VERSION 5.7 ;
  NOWIREEXTENSIONATPIN ON ;
  DIVIDERCHAR "/" ;
  BUSBITCHARS "[]" ;
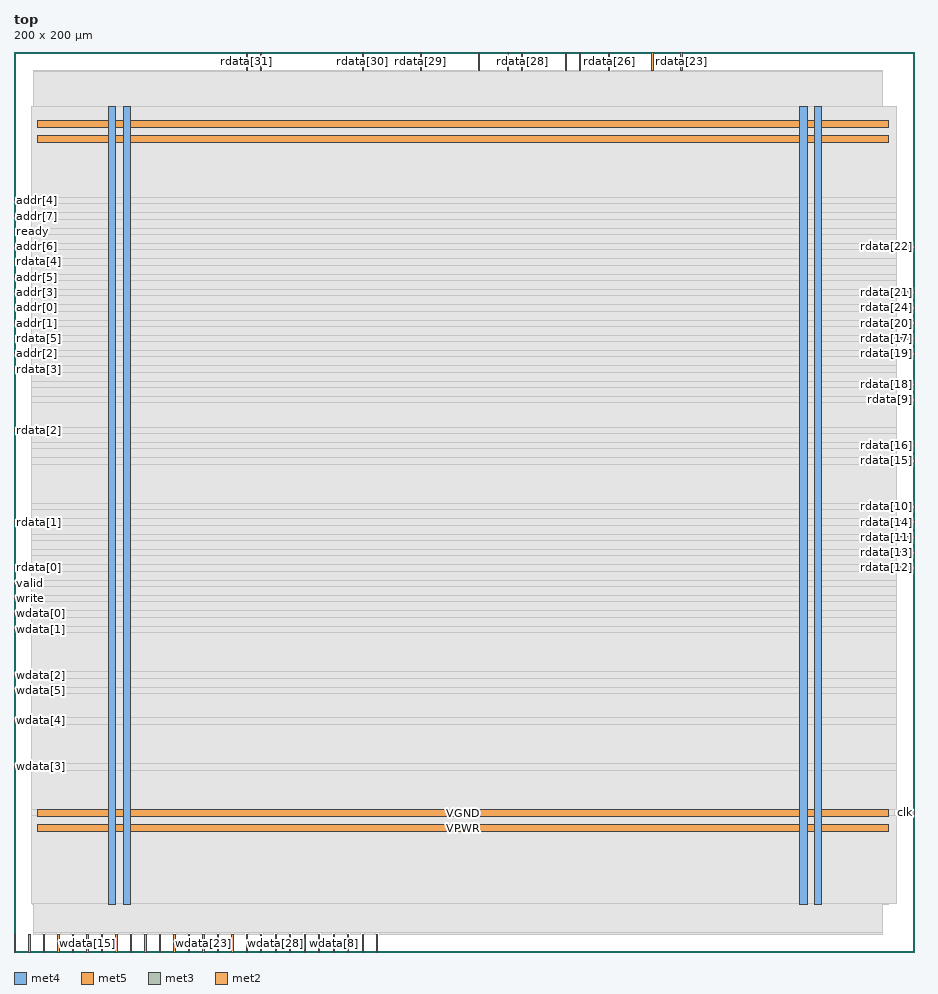
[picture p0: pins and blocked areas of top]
MACRO top
  CLASS BLOCK ;
  FOREIGN top ;
  ORIGIN 0.000 0.000 ;
  SIZE 200.000 BY 200.000 ;
  PIN VGND
    DIRECTION INOUT ;
    USE GROUND ;
    PORT
      LAYER met4 ;
        RECT 24.340 10.640 25.940 187.920 ;
    END
    PORT
      LAYER met4 ;
        RECT 177.940 10.640 179.540 187.920 ;
    END
    PORT
      LAYER met5 ;
        RECT 5.280 30.030 194.360 31.630 ;
    END
    PORT
      LAYER met5 ;
        RECT 5.280 183.210 194.360 184.810 ;
    END
  END VGND
  PIN VPWR
    DIRECTION INOUT ;
    USE POWER ;
    PORT
      LAYER met4 ;
        RECT 21.040 10.640 22.640 187.920 ;
    END
    PORT
      LAYER met4 ;
        RECT 174.640 10.640 176.240 187.920 ;
    END
    PORT
      LAYER met5 ;
        RECT 5.280 26.730 194.360 28.330 ;
    END
    PORT
      LAYER met5 ;
        RECT 5.280 179.910 194.360 181.510 ;
    END
  END VPWR
  PIN addr[0]
    DIRECTION INPUT ;
    USE SIGNAL ;
    ANTENNAGATEAREA 0.196500 ;
    PORT
      LAYER met3 ;
        RECT 0.000 142.840 4.000 143.440 ;
    END
  END addr[0]
  PIN addr[1]
    DIRECTION INPUT ;
    USE SIGNAL ;
    ANTENNAGATEAREA 0.196500 ;
    PORT
      LAYER met3 ;
        RECT 0.000 139.440 4.000 140.040 ;
    END
  END addr[1]
  PIN addr[2]
    DIRECTION INPUT ;
    USE SIGNAL ;
    ANTENNAGATEAREA 0.196500 ;
    PORT
      LAYER met3 ;
        RECT 0.000 132.640 4.000 133.240 ;
    END
  END addr[2]
  PIN addr[3]
    DIRECTION INPUT ;
    USE SIGNAL ;
    ANTENNAGATEAREA 0.196500 ;
    PORT
      LAYER met3 ;
        RECT 0.000 146.240 4.000 146.840 ;
    END
  END addr[3]
  PIN addr[4]
    DIRECTION INPUT ;
    USE SIGNAL ;
    ANTENNAGATEAREA 0.196500 ;
    PORT
      LAYER met3 ;
        RECT 0.000 166.640 4.000 167.240 ;
    END
  END addr[4]
  PIN addr[5]
    DIRECTION INPUT ;
    USE SIGNAL ;
    ANTENNAGATEAREA 0.196500 ;
    PORT
      LAYER met3 ;
        RECT 0.000 149.640 4.000 150.240 ;
    END
  END addr[5]
  PIN addr[6]
    DIRECTION INPUT ;
    USE SIGNAL ;
    ANTENNAGATEAREA 0.196500 ;
    PORT
      LAYER met3 ;
        RECT 0.000 156.440 4.000 157.040 ;
    END
  END addr[6]
  PIN addr[7]
    DIRECTION INPUT ;
    USE SIGNAL ;
    ANTENNAGATEAREA 0.196500 ;
    PORT
      LAYER met3 ;
        RECT 0.000 163.240 4.000 163.840 ;
    END
  END addr[7]
  PIN clk
    DIRECTION INPUT ;
    USE SIGNAL ;
    ANTENNAGATEAREA 0.852000 ;
    PORT
      LAYER met3 ;
        RECT 196.000 30.640 200.000 31.240 ;
    END
  END clk
  PIN rdata[0]
    DIRECTION OUTPUT ;
    USE SIGNAL ;
    ANTENNADIFFAREA 0.445500 ;
    PORT
      LAYER met3 ;
        RECT 0.000 85.040 4.000 85.640 ;
    END
  END rdata[0]
  PIN rdata[10]
    DIRECTION OUTPUT ;
    USE SIGNAL ;
    ANTENNADIFFAREA 0.445500 ;
    PORT
      LAYER met3 ;
        RECT 196.000 98.640 200.000 99.240 ;
    END
  END rdata[10]
  PIN rdata[11]
    DIRECTION OUTPUT ;
    USE SIGNAL ;
    ANTENNADIFFAREA 0.445500 ;
    PORT
      LAYER met3 ;
        RECT 196.000 91.840 200.000 92.440 ;
    END
  END rdata[11]
  PIN rdata[12]
    DIRECTION OUTPUT ;
    USE SIGNAL ;
    ANTENNADIFFAREA 0.445500 ;
    PORT
      LAYER met3 ;
        RECT 196.000 85.040 200.000 85.640 ;
    END
  END rdata[12]
  PIN rdata[13]
    DIRECTION OUTPUT ;
    USE SIGNAL ;
    ANTENNADIFFAREA 0.445500 ;
    PORT
      LAYER met3 ;
        RECT 196.000 88.440 200.000 89.040 ;
    END
  END rdata[13]
  PIN rdata[14]
    DIRECTION OUTPUT ;
    USE SIGNAL ;
    ANTENNADIFFAREA 0.445500 ;
    PORT
      LAYER met3 ;
        RECT 196.000 95.240 200.000 95.840 ;
    END
  END rdata[14]
  PIN rdata[15]
    DIRECTION OUTPUT ;
    USE SIGNAL ;
    ANTENNADIFFAREA 0.445500 ;
    PORT
      LAYER met3 ;
        RECT 196.000 108.840 200.000 109.440 ;
    END
  END rdata[15]
  PIN rdata[16]
    DIRECTION OUTPUT ;
    USE SIGNAL ;
    ANTENNADIFFAREA 0.445500 ;
    PORT
      LAYER met3 ;
        RECT 196.000 112.240 200.000 112.840 ;
    END
  END rdata[16]
  PIN rdata[17]
    DIRECTION OUTPUT ;
    USE SIGNAL ;
    ANTENNADIFFAREA 0.445500 ;
    PORT
      LAYER met3 ;
        RECT 196.000 136.040 200.000 136.640 ;
    END
  END rdata[17]
  PIN rdata[18]
    DIRECTION OUTPUT ;
    USE SIGNAL ;
    ANTENNADIFFAREA 0.445500 ;
    PORT
      LAYER met3 ;
        RECT 196.000 125.840 200.000 126.440 ;
    END
  END rdata[18]
  PIN rdata[19]
    DIRECTION OUTPUT ;
    USE SIGNAL ;
    ANTENNADIFFAREA 0.445500 ;
    PORT
      LAYER met3 ;
        RECT 196.000 132.640 200.000 133.240 ;
    END
  END rdata[19]
  PIN rdata[1]
    DIRECTION OUTPUT ;
    USE SIGNAL ;
    ANTENNADIFFAREA 0.445500 ;
    PORT
      LAYER met3 ;
        RECT 0.000 95.240 4.000 95.840 ;
    END
  END rdata[1]
  PIN rdata[20]
    DIRECTION OUTPUT ;
    USE SIGNAL ;
    ANTENNADIFFAREA 0.445500 ;
    PORT
      LAYER met3 ;
        RECT 196.000 139.440 200.000 140.040 ;
    END
  END rdata[20]
  PIN rdata[21]
    DIRECTION OUTPUT ;
    USE SIGNAL ;
    ANTENNADIFFAREA 0.445500 ;
    PORT
      LAYER met3 ;
        RECT 196.000 146.240 200.000 146.840 ;
    END
  END rdata[21]
  PIN rdata[22]
    DIRECTION OUTPUT ;
    USE SIGNAL ;
    ANTENNADIFFAREA 0.445500 ;
    PORT
      LAYER met3 ;
        RECT 196.000 156.440 200.000 157.040 ;
    END
  END rdata[22]
  PIN rdata[23]
    DIRECTION OUTPUT ;
    USE SIGNAL ;
    ANTENNADIFFAREA 0.445500 ;
    PORT
      LAYER met2 ;
        RECT 148.210 196.000 148.490 200.000 ;
    END
  END rdata[23]
  PIN rdata[24]
    DIRECTION OUTPUT ;
    USE SIGNAL ;
    ANTENNADIFFAREA 0.445500 ;
    PORT
      LAYER met3 ;
        RECT 196.000 142.840 200.000 143.440 ;
    END
  END rdata[24]
  PIN rdata[25]
    DIRECTION OUTPUT ;
    USE SIGNAL ;
    ANTENNADIFFAREA 0.445500 ;
    PORT
      LAYER met2 ;
        RECT 122.450 196.000 122.730 200.000 ;
    END
  END rdata[25]
  PIN rdata[26]
    DIRECTION OUTPUT ;
    USE SIGNAL ;
    ANTENNADIFFAREA 0.445500 ;
    PORT
      LAYER met2 ;
        RECT 132.110 196.000 132.390 200.000 ;
    END
  END rdata[26]
  PIN rdata[27]
    DIRECTION OUTPUT ;
    USE SIGNAL ;
    ANTENNADIFFAREA 0.445500 ;
    PORT
      LAYER met2 ;
        RECT 109.570 196.000 109.850 200.000 ;
    END
  END rdata[27]
  PIN rdata[28]
    DIRECTION OUTPUT ;
    USE SIGNAL ;
    ANTENNADIFFAREA 0.445500 ;
    PORT
      LAYER met2 ;
        RECT 112.790 196.000 113.070 200.000 ;
    END
  END rdata[28]
  PIN rdata[29]
    DIRECTION OUTPUT ;
    USE SIGNAL ;
    ANTENNADIFFAREA 0.445500 ;
    PORT
      LAYER met2 ;
        RECT 90.250 196.000 90.530 200.000 ;
    END
  END rdata[29]
  PIN rdata[2]
    DIRECTION OUTPUT ;
    USE SIGNAL ;
    ANTENNADIFFAREA 0.445500 ;
    PORT
      LAYER met3 ;
        RECT 0.000 115.640 4.000 116.240 ;
    END
  END rdata[2]
  PIN rdata[30]
    DIRECTION OUTPUT ;
    USE SIGNAL ;
    ANTENNADIFFAREA 0.445500 ;
    PORT
      LAYER met2 ;
        RECT 77.370 196.000 77.650 200.000 ;
    END
  END rdata[30]
  PIN rdata[31]
    DIRECTION OUTPUT ;
    USE SIGNAL ;
    ANTENNADIFFAREA 0.445500 ;
    PORT
      LAYER met2 ;
        RECT 51.610 196.000 51.890 200.000 ;
    END
  END rdata[31]
  PIN rdata[3]
    DIRECTION OUTPUT ;
    USE SIGNAL ;
    ANTENNADIFFAREA 0.445500 ;
    PORT
      LAYER met3 ;
        RECT 0.000 129.240 4.000 129.840 ;
    END
  END rdata[3]
  PIN rdata[4]
    DIRECTION OUTPUT ;
    USE SIGNAL ;
    ANTENNADIFFAREA 0.445500 ;
    PORT
      LAYER met3 ;
        RECT 0.000 153.040 4.000 153.640 ;
    END
  END rdata[4]
  PIN rdata[5]
    DIRECTION OUTPUT ;
    USE SIGNAL ;
    ANTENNADIFFAREA 0.445500 ;
    PORT
      LAYER met3 ;
        RECT 0.000 136.040 4.000 136.640 ;
    END
  END rdata[5]
  PIN rdata[6]
    DIRECTION OUTPUT ;
    USE SIGNAL ;
    ANTENNADIFFAREA 0.445500 ;
    PORT
      LAYER met2 ;
        RECT 54.830 196.000 55.110 200.000 ;
    END
  END rdata[6]
  PIN rdata[7]
    DIRECTION OUTPUT ;
    USE SIGNAL ;
    ANTENNADIFFAREA 0.445500 ;
    PORT
      LAYER met2 ;
        RECT 103.130 196.000 103.410 200.000 ;
    END
  END rdata[7]
  PIN rdata[8]
    DIRECTION OUTPUT ;
    USE SIGNAL ;
    ANTENNADIFFAREA 0.445500 ;
    PORT
      LAYER met2 ;
        RECT 125.670 196.000 125.950 200.000 ;
    END
  END rdata[8]
  PIN rdata[9]
    DIRECTION OUTPUT ;
    USE SIGNAL ;
    ANTENNADIFFAREA 0.445500 ;
    PORT
      LAYER met3 ;
        RECT 196.000 122.440 200.000 123.040 ;
    END
  END rdata[9]
  PIN ready
    DIRECTION OUTPUT ;
    USE SIGNAL ;
    PORT
      LAYER met3 ;
        RECT 0.000 159.840 4.000 160.440 ;
    END
  END ready
  PIN rst
    DIRECTION INPUT ;
    USE SIGNAL ;
    ANTENNAGATEAREA 0.213000 ;
    PORT
      LAYER met2 ;
        RECT 141.770 196.000 142.050 200.000 ;
    END
  END rst
  PIN valid
    DIRECTION INPUT ;
    USE SIGNAL ;
    ANTENNAGATEAREA 0.213000 ;
    PORT
      LAYER met3 ;
        RECT 0.000 81.640 4.000 82.240 ;
    END
  END valid
  PIN wdata[0]
    DIRECTION INPUT ;
    USE SIGNAL ;
    ANTENNAGATEAREA 0.196500 ;
    PORT
      LAYER met3 ;
        RECT 0.000 74.840 4.000 75.440 ;
    END
  END wdata[0]
  PIN wdata[10]
    DIRECTION INPUT ;
    USE SIGNAL ;
    PORT
      LAYER met2 ;
        RECT 3.310 0.000 3.590 4.000 ;
    END
  END wdata[10]
  PIN wdata[11]
    DIRECTION INPUT ;
    USE SIGNAL ;
    PORT
      LAYER met2 ;
        RECT 6.530 0.000 6.810 4.000 ;
    END
  END wdata[11]
  PIN wdata[12]
    DIRECTION INPUT ;
    USE SIGNAL ;
    PORT
      LAYER met2 ;
        RECT 9.750 0.000 10.030 4.000 ;
    END
  END wdata[12]
  PIN wdata[13]
    DIRECTION INPUT ;
    USE SIGNAL ;
    PORT
      LAYER met2 ;
        RECT 12.970 0.000 13.250 4.000 ;
    END
  END wdata[13]
  PIN wdata[14]
    DIRECTION INPUT ;
    USE SIGNAL ;
    PORT
      LAYER met2 ;
        RECT 80.590 0.000 80.870 4.000 ;
    END
  END wdata[14]
  PIN wdata[15]
    DIRECTION INPUT ;
    USE SIGNAL ;
    PORT
      LAYER met2 ;
        RECT 16.190 0.000 16.470 4.000 ;
    END
  END wdata[15]
  PIN wdata[16]
    DIRECTION INPUT ;
    USE SIGNAL ;
    PORT
      LAYER met2 ;
        RECT 19.410 0.000 19.690 4.000 ;
    END
  END wdata[16]
  PIN wdata[17]
    DIRECTION INPUT ;
    USE SIGNAL ;
    PORT
      LAYER met2 ;
        RECT 22.630 0.000 22.910 4.000 ;
    END
  END wdata[17]
  PIN wdata[18]
    DIRECTION INPUT ;
    USE SIGNAL ;
    PORT
      LAYER met2 ;
        RECT 25.850 0.000 26.130 4.000 ;
    END
  END wdata[18]
  PIN wdata[19]
    DIRECTION INPUT ;
    USE SIGNAL ;
    PORT
      LAYER met2 ;
        RECT 29.070 0.000 29.350 4.000 ;
    END
  END wdata[19]
  PIN wdata[1]
    DIRECTION INPUT ;
    USE SIGNAL ;
    ANTENNAGATEAREA 0.196500 ;
    PORT
      LAYER met3 ;
        RECT 0.000 71.440 4.000 72.040 ;
    END
  END wdata[1]
  PIN wdata[20]
    DIRECTION INPUT ;
    USE SIGNAL ;
    PORT
      LAYER met2 ;
        RECT 32.290 0.000 32.570 4.000 ;
    END
  END wdata[20]
  PIN wdata[21]
    DIRECTION INPUT ;
    USE SIGNAL ;
    PORT
      LAYER met2 ;
        RECT 35.510 0.000 35.790 4.000 ;
    END
  END wdata[21]
  PIN wdata[22]
    DIRECTION INPUT ;
    USE SIGNAL ;
    PORT
      LAYER met2 ;
        RECT 38.730 0.000 39.010 4.000 ;
    END
  END wdata[22]
  PIN wdata[23]
    DIRECTION INPUT ;
    USE SIGNAL ;
    PORT
      LAYER met2 ;
        RECT 41.950 0.000 42.230 4.000 ;
    END
  END wdata[23]
  PIN wdata[24]
    DIRECTION INPUT ;
    USE SIGNAL ;
    PORT
      LAYER met2 ;
        RECT 0.090 0.000 0.370 4.000 ;
    END
  END wdata[24]
  PIN wdata[25]
    DIRECTION INPUT ;
    USE SIGNAL ;
    PORT
      LAYER met2 ;
        RECT 48.390 0.000 48.670 4.000 ;
    END
  END wdata[25]
  PIN wdata[26]
    DIRECTION INPUT ;
    USE SIGNAL ;
    PORT
      LAYER met2 ;
        RECT 64.490 0.000 64.770 4.000 ;
    END
  END wdata[26]
  PIN wdata[27]
    DIRECTION INPUT ;
    USE SIGNAL ;
    PORT
      LAYER met2 ;
        RECT 54.830 0.000 55.110 4.000 ;
    END
  END wdata[27]
  PIN wdata[28]
    DIRECTION INPUT ;
    USE SIGNAL ;
    PORT
      LAYER met2 ;
        RECT 58.050 0.000 58.330 4.000 ;
    END
  END wdata[28]
  PIN wdata[29]
    DIRECTION INPUT ;
    USE SIGNAL ;
    PORT
      LAYER met2 ;
        RECT 61.270 0.000 61.550 4.000 ;
    END
  END wdata[29]
  PIN wdata[2]
    DIRECTION INPUT ;
    USE SIGNAL ;
    ANTENNAGATEAREA 0.196500 ;
    PORT
      LAYER met3 ;
        RECT 0.000 61.240 4.000 61.840 ;
    END
  END wdata[2]
  PIN wdata[30]
    DIRECTION INPUT ;
    USE SIGNAL ;
    PORT
      LAYER met2 ;
        RECT 77.370 0.000 77.650 4.000 ;
    END
  END wdata[30]
  PIN wdata[31]
    DIRECTION INPUT ;
    USE SIGNAL ;
    PORT
      LAYER met2 ;
        RECT 67.710 0.000 67.990 4.000 ;
    END
  END wdata[31]
  PIN wdata[3]
    DIRECTION INPUT ;
    USE SIGNAL ;
    ANTENNAGATEAREA 0.196500 ;
    PORT
      LAYER met3 ;
        RECT 0.000 40.840 4.000 41.440 ;
    END
  END wdata[3]
  PIN wdata[4]
    DIRECTION INPUT ;
    USE SIGNAL ;
    ANTENNAGATEAREA 0.196500 ;
    PORT
      LAYER met3 ;
        RECT 0.000 51.040 4.000 51.640 ;
    END
  END wdata[4]
  PIN wdata[5]
    DIRECTION INPUT ;
    USE SIGNAL ;
    ANTENNAGATEAREA 0.196500 ;
    PORT
      LAYER met3 ;
        RECT 0.000 57.840 4.000 58.440 ;
    END
  END wdata[5]
  PIN wdata[6]
    DIRECTION INPUT ;
    USE SIGNAL ;
    ANTENNAGATEAREA 0.196500 ;
    PORT
      LAYER met2 ;
        RECT 51.610 0.000 51.890 4.000 ;
    END
  END wdata[6]
  PIN wdata[7]
    DIRECTION INPUT ;
    USE SIGNAL ;
    ANTENNAGATEAREA 0.196500 ;
    PORT
      LAYER met2 ;
        RECT 45.170 0.000 45.450 4.000 ;
    END
  END wdata[7]
  PIN wdata[8]
    DIRECTION INPUT ;
    USE SIGNAL ;
    PORT
      LAYER met2 ;
        RECT 70.930 0.000 71.210 4.000 ;
    END
  END wdata[8]
  PIN wdata[9]
    DIRECTION INPUT ;
    USE SIGNAL ;
    PORT
      LAYER met2 ;
        RECT 74.150 0.000 74.430 4.000 ;
    END
  END wdata[9]
  PIN write
    DIRECTION INPUT ;
    USE SIGNAL ;
    ANTENNAGATEAREA 0.196500 ;
    PORT
      LAYER met3 ;
        RECT 0.000 78.240 4.000 78.840 ;
    END
  END write
  OBS
      LAYER nwell ;
        RECT 5.330 10.795 194.310 187.870 ;
      LAYER li1 ;
        RECT 5.520 10.795 194.120 187.765 ;
      LAYER met1 ;
        RECT 4.210 10.640 194.420 187.920 ;
      LAYER met2 ;
        RECT 4.230 195.720 51.330 196.000 ;
        RECT 52.170 195.720 54.550 196.000 ;
        RECT 55.390 195.720 77.090 196.000 ;
        RECT 77.930 195.720 89.970 196.000 ;
        RECT 90.810 195.720 102.850 196.000 ;
        RECT 103.690 195.720 109.290 196.000 ;
        RECT 110.130 195.720 112.510 196.000 ;
        RECT 113.350 195.720 122.170 196.000 ;
        RECT 123.010 195.720 125.390 196.000 ;
        RECT 126.230 195.720 131.830 196.000 ;
        RECT 132.670 195.720 141.490 196.000 ;
        RECT 142.330 195.720 147.930 196.000 ;
        RECT 148.770 195.720 193.110 196.000 ;
        RECT 4.230 4.280 193.110 195.720 ;
        RECT 4.230 4.000 6.250 4.280 ;
        RECT 7.090 4.000 9.470 4.280 ;
        RECT 10.310 4.000 12.690 4.280 ;
        RECT 13.530 4.000 15.910 4.280 ;
        RECT 16.750 4.000 19.130 4.280 ;
        RECT 19.970 4.000 22.350 4.280 ;
        RECT 23.190 4.000 25.570 4.280 ;
        RECT 26.410 4.000 28.790 4.280 ;
        RECT 29.630 4.000 32.010 4.280 ;
        RECT 32.850 4.000 35.230 4.280 ;
        RECT 36.070 4.000 38.450 4.280 ;
        RECT 39.290 4.000 41.670 4.280 ;
        RECT 42.510 4.000 44.890 4.280 ;
        RECT 45.730 4.000 48.110 4.280 ;
        RECT 48.950 4.000 51.330 4.280 ;
        RECT 52.170 4.000 54.550 4.280 ;
        RECT 55.390 4.000 57.770 4.280 ;
        RECT 58.610 4.000 60.990 4.280 ;
        RECT 61.830 4.000 64.210 4.280 ;
        RECT 65.050 4.000 67.430 4.280 ;
        RECT 68.270 4.000 70.650 4.280 ;
        RECT 71.490 4.000 73.870 4.280 ;
        RECT 74.710 4.000 77.090 4.280 ;
        RECT 77.930 4.000 80.310 4.280 ;
        RECT 81.150 4.000 193.110 4.280 ;
      LAYER met3 ;
        RECT 3.990 167.640 196.000 187.845 ;
        RECT 4.400 166.240 196.000 167.640 ;
        RECT 3.990 164.240 196.000 166.240 ;
        RECT 4.400 162.840 196.000 164.240 ;
        RECT 3.990 160.840 196.000 162.840 ;
        RECT 4.400 159.440 196.000 160.840 ;
        RECT 3.990 157.440 196.000 159.440 ;
        RECT 4.400 156.040 195.600 157.440 ;
        RECT 3.990 154.040 196.000 156.040 ;
        RECT 4.400 152.640 196.000 154.040 ;
        RECT 3.990 150.640 196.000 152.640 ;
        RECT 4.400 149.240 196.000 150.640 ;
        RECT 3.990 147.240 196.000 149.240 ;
        RECT 4.400 145.840 195.600 147.240 ;
        RECT 3.990 143.840 196.000 145.840 ;
        RECT 4.400 142.440 195.600 143.840 ;
        RECT 3.990 140.440 196.000 142.440 ;
        RECT 4.400 139.040 195.600 140.440 ;
        RECT 3.990 137.040 196.000 139.040 ;
        RECT 4.400 135.640 195.600 137.040 ;
        RECT 3.990 133.640 196.000 135.640 ;
        RECT 4.400 132.240 195.600 133.640 ;
        RECT 3.990 130.240 196.000 132.240 ;
        RECT 4.400 128.840 196.000 130.240 ;
        RECT 3.990 126.840 196.000 128.840 ;
        RECT 3.990 125.440 195.600 126.840 ;
        RECT 3.990 123.440 196.000 125.440 ;
        RECT 3.990 122.040 195.600 123.440 ;
        RECT 3.990 116.640 196.000 122.040 ;
        RECT 4.400 115.240 196.000 116.640 ;
        RECT 3.990 113.240 196.000 115.240 ;
        RECT 3.990 111.840 195.600 113.240 ;
        RECT 3.990 109.840 196.000 111.840 ;
        RECT 3.990 108.440 195.600 109.840 ;
        RECT 3.990 99.640 196.000 108.440 ;
        RECT 3.990 98.240 195.600 99.640 ;
        RECT 3.990 96.240 196.000 98.240 ;
        RECT 4.400 94.840 195.600 96.240 ;
        RECT 3.990 92.840 196.000 94.840 ;
        RECT 3.990 91.440 195.600 92.840 ;
        RECT 3.990 89.440 196.000 91.440 ;
        RECT 3.990 88.040 195.600 89.440 ;
        RECT 3.990 86.040 196.000 88.040 ;
        RECT 4.400 84.640 195.600 86.040 ;
        RECT 3.990 82.640 196.000 84.640 ;
        RECT 4.400 81.240 196.000 82.640 ;
        RECT 3.990 79.240 196.000 81.240 ;
        RECT 4.400 77.840 196.000 79.240 ;
        RECT 3.990 75.840 196.000 77.840 ;
        RECT 4.400 74.440 196.000 75.840 ;
        RECT 3.990 72.440 196.000 74.440 ;
        RECT 4.400 71.040 196.000 72.440 ;
        RECT 3.990 62.240 196.000 71.040 ;
        RECT 4.400 60.840 196.000 62.240 ;
        RECT 3.990 58.840 196.000 60.840 ;
        RECT 4.400 57.440 196.000 58.840 ;
        RECT 3.990 52.040 196.000 57.440 ;
        RECT 4.400 50.640 196.000 52.040 ;
        RECT 3.990 41.840 196.000 50.640 ;
        RECT 4.400 40.440 196.000 41.840 ;
        RECT 3.990 31.640 196.000 40.440 ;
        RECT 3.990 30.240 195.600 31.640 ;
        RECT 3.990 10.715 196.000 30.240 ;
  END
END top
END LIBRARY

